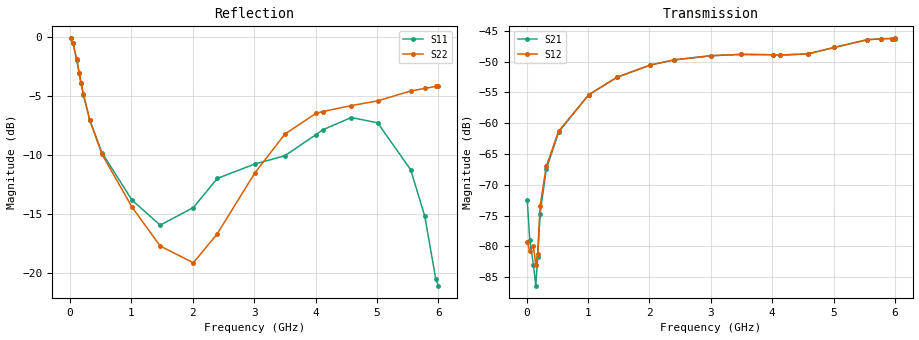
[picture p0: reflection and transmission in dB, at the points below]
!Agilent Technologies,N5230A,MY45001650,A.07.50.48
!Agilent N5230A: A.07.50.48
!Date: Saturday, July 08, 2017 15:55:44
!Correction: S11(Full 2 Port(1,2))
!S21(Full 2 Port(1,2))
!S12(Full 2 Port(1,2))
!S22(Full 2 Port(1,2))
!S2P File: Measurements: S11, S21, S12, S22:
# Hz S  dB  R 50
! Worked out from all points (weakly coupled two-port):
!   600 points, 10 MHz to 6 GHz, reference 50 ohm
!   highest |S21| = -46.24 dB at 5.96 GHz (marker M1); lowest = -86.4 dB at 150 MHz (marker M2)
!   lowest |S11| = -21.1 dB at 6 GHz (marker M3), VSWR 1.19, Z = 59.6 + j1.18 ohm
!   |S11| at or under -10 dB: 548.3 MHz to 3.538 GHz (2.99 GHz wide, 146 % of centre); 5.439 GHz to end of sweep
!   |S22| runs from -19.6 to -0.1 dB; largest |S21 - S12| = 0.00034
!   S11 on the Smith chart (normalised r, x): 10 MHz: 2, -19; 110 MHz: 0.50, -1.81; 320 MHz: 0.52, -0.54; 2.4 GHz: 0.61, +0.09; 4.12 GHz: 1.66, +0.93; 6 GHz: 1.19, +0.02
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1e7  -0.11 -5.9  -72.42 -77.1  -79.23 127.1  -0.11 -5.5
5e7  -0.51 -27.6  -78.91 63.5  -80.76 42.4  -0.49 -25.4
1.1e8  -1.94 -55.1  -82.96 25.8  -79.95 49.1  -1.89 -50.6
1.5e8  -3.05 -69.6  -86.40 51.7  -83.09 74.1  -3.01 -63.7
1.8e8  -3.91 -79.0  -81.66 110.7  -81.31 110.4  -3.86 -72.3
2.2e8  -4.88 -89.9  -74.67 110.0  -73.40 108.1  -4.85 -81.9
3.2e8  -7.01 -112.0  -67.48 92.7  -67.00 94.5  -6.99 -100.4
5.2e8  -9.79 -143.3  -61.46 65.7  -61.30 66.0  -9.92 -125.0
1.01e9  -13.81 178.4  -55.39 15.6  -55.39 15.2  -14.40 -155.2
1.47e9  -15.94 167.5  -52.54 -26.7  -52.54 -26.5  -17.71 -170.0
2.01e9  -14.45 174.7  -50.55 -75.8  -50.56 -75.9  -19.13 -169.9
2.4e9  -11.98 163.8  -49.71 -111.5  -49.71 -111.5  -16.67 -175.1
3.01e9  -10.76 131.2  -49.04 -168.4  -49.01 -168.2  -11.53 168.5
3.5e9  -10.06 89.5  -48.81 145.4  -48.82 145.5  -8.23 154.9
4.01e9  -8.26 42.7  -48.87 99.4  -48.88 99.3  -6.46 139.6
4.12e9  -7.86 35.2  -48.93 90.3  -48.91 90.3  -6.31 136.5
4.58e9  -6.82 10.5  -48.74 55.5  -48.74 55.5  -5.81 119.6
5.01e9  -7.26 -5.8  -47.69 22.2  -47.68 22.5  -5.41 101.6
5.55e9  -11.24 -20.4  -46.43 -27.5  -46.42 -27.4  -4.57 76.2
5.78e9  -15.18 -20.5  -46.27 -48.8  -46.29 -48.7  -4.35 64.1
5.96e9  -20.53 -2.4  -46.24 -64.8  -46.24 -65.0  -4.18 54.3
6e9  -21.07 6.4  -46.27 -68.5  -46.21 -68.4  -4.16 52.0
